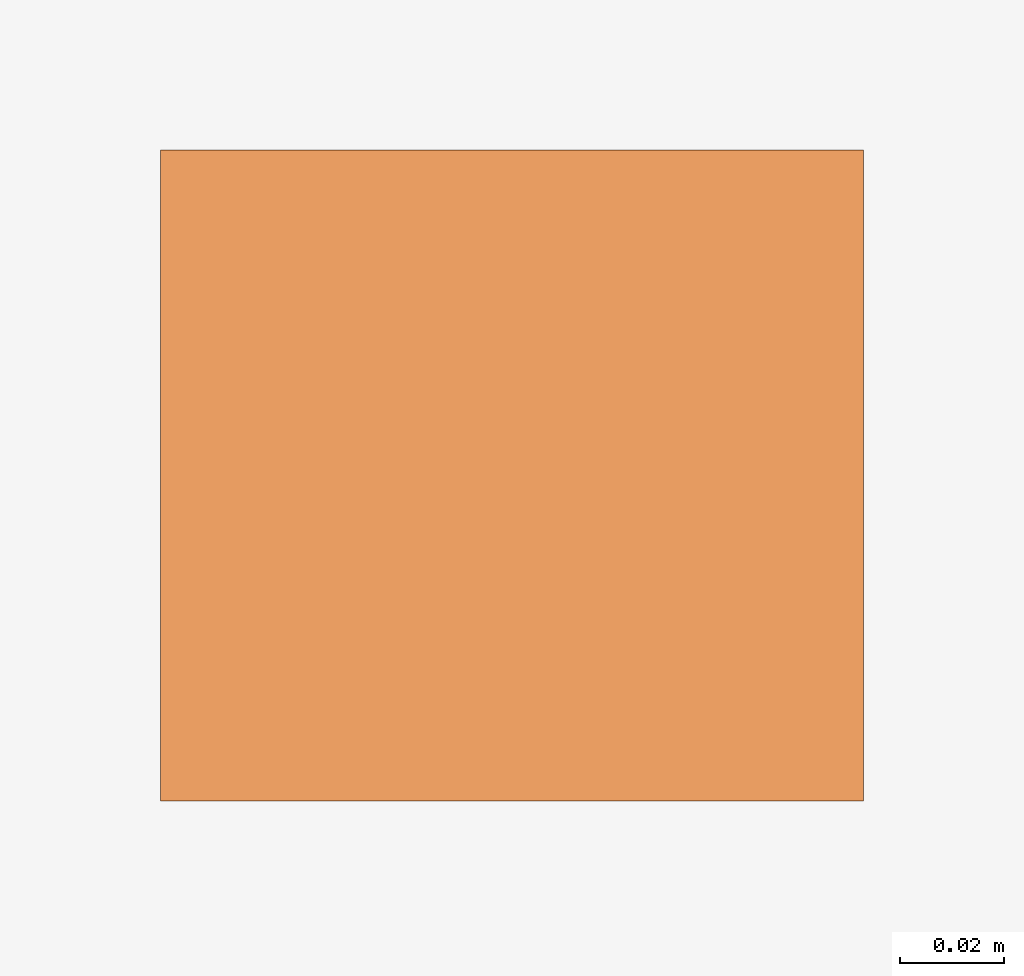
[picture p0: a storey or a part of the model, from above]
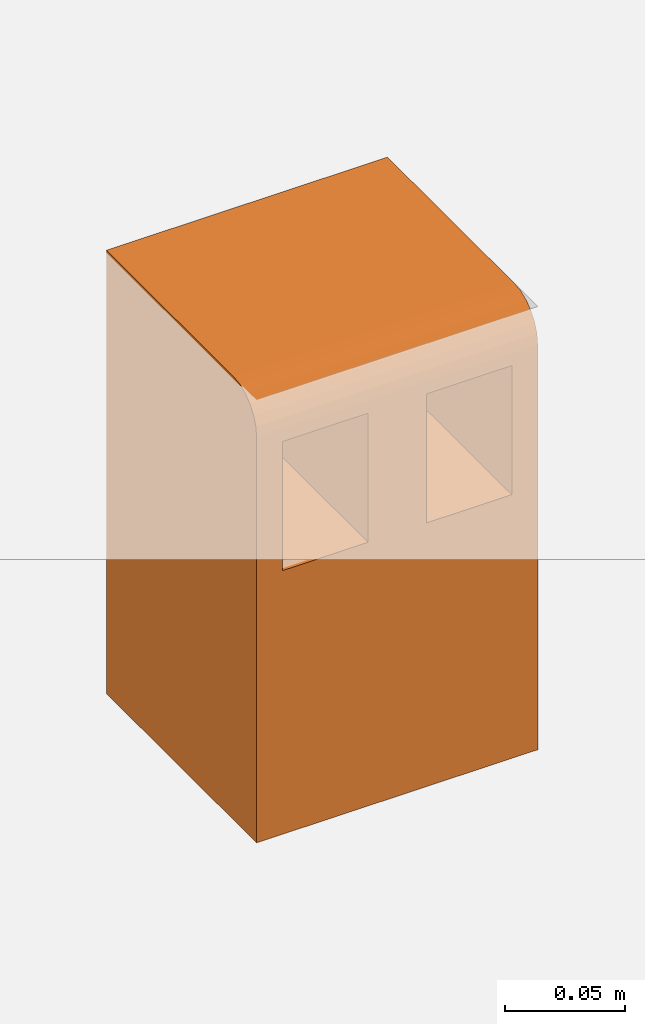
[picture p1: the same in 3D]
Properties of the parts of a building model (IFC2X3)

# File
Description: ViewDefinition [CoordinationView]
File name: 23453 - CFD kerb Outlet Bull Nose.ifc
Time: 2013-10-16T12:22:15
Written by: Autodesk Revit 2013
Made in: 20120221_2030(x64)

# IfcProject, Project Number
LongName: Project Name; Phase: Project Status

# IfcSite, Default
RefLatitude: 42, 21, 30, 344238; RefLongitude: -71, -3, -35, -194702; RefElevation: 0 mm

# IfcBuilding
Pset_BuildingCommon - NumberOfStoreys: 1
Other - Project Address: ## Street City, State Zip; Project Name: Project Name; Project Issue Date: Issue Date; Project Number: Project Number; Client Name: Owner; Project Status: Project Status

# IfcBuildingStorey, Level 1
LongName: Level 1; Elevation: 0 mm
Graphics - Symbol: M_Level Head - Circle: M_Level Head - Circle; Color: 0; Symbol at End 2 Default: yes; Line Pattern: Center; Symbol at End 1 Default: no; Line Weight: 1
Constraints - Elevation Base: 0; Elevation: 0 mm
Identity Data - Name: Level 1; Structural: no; Building Story: yes
Dimensions - Computation Height: 0 mm

# IfcBuildingElementProxy: 23453 - CFD kerb Outlet Bull Nose, Civil-Drainage-Channel-ACO-MultiDrain-M100D-Channel-System:23453 - CFD kerb Outlet Bull Nose:23453 - CFD kerb Outlet Bull Nose:1089344
In: Level 1
Material: Grey Polymer Concrete
Construction - 12673 - Grating - Intercept - Ductile Iron - 500mm Long: no; 12667 - Grating - Perforated - Galvanised Steel - 500mm Long: no; 12680 - Grating - Heelguard™ - Composite Black - 500mm Long: no; 23405 - Grating - Heelguard™ - Ductile Iron - 500mm Long: no; 12656 - Grating - Perforated - Galvanised Steel - 1000mm long: no; 23404 - Universal Endcap - Female End: no; 12619 - Grating - Mesh - Galvanised Steel - 500mm Long: no; 23408 - Grating - Slotted - Ductile Iron - 500mm Long: no; 12610 - Grating - Slotted - Galvanised Steel - 1000mm Long: no; 12666 - Grating - Perforated - Galvanised Steel - 1000mm Long: no; 23406 - Grating - Solid Cover - Ductile Iron - 500mm Long: no; 23409 - Grating - ATec coated - Heelguard™ - Ductile Iron - 500mm Long: no; 12618 - Grating - Mesh - Galvanised Steel - 1000mm Long: no; 23404 - Universal Endcap - Male End: no; 12657 - Grating - Perforated - Galvanised Steel - 500mm long: no; 12611 - Grating - Slotted - Galvanised Steel - 500mm Long: no; 12614 - Grating - Slotted - Galvanised Steel - 1000mm Long: no; 12615 - Grating - Slotted - Galvanised Steel - 500mm Long: no; Shallow Depth Channel: no; 23452 - Kerb Outlet Half Batter: no; Sloping Channel: no; Constant Depth Channel: no; 23453 - Kerb Outlet Bull Nose: yes; 23451 - Downpipe connector 100mm Depth: no; Constant Depth Junction Channel: no; 23450 - Downpipe connector 75mm Depth: no; Sump Unit: no; Shallow Depth Channel with seal: no; Grating 1000mm: no
Constraints - Level: Level: Level 1; Moves With Nearby Elements: no
Dimensions - Length: 125 mm; Volume: 3179082 mm3; EndCap Position: 125 mm; Custom_Value_Length: 875 mm; FloorCut_Length: -125 mm; EndCap_Female_Height: 200 mm; SlopingInvertDepth: 125 mm; SlopingEndOverallDepth: 200 mm; SlopingEndInvertDepth: 130 mm; FloorCut_HorPosition: 67.5 mm; ShallowOverallDepth: 75 mm; SlopingOverallDepth: 195 mm; FloorCut_Width: 135 mm; FloorCut_Depth: 225 mm; EndCap_Height: 200 mm; Endcap_Void_Depth: 6000 mm; ShallowInvDepth: 55 mm; Length Drain: -1000 mm; InvDepth: 80 mm; Depth: 150 mm
Phasing - Phase Created: New Construction
Pset_BuildingElementProxyCommon - Reference: 23453 - CFD kerb Outlet Bull Nose
Model Properties - End Cap Product code 23404: N/A; Grating Product code 12614: N/A; Grating Product code 23406: N/A; Grating Product code 12666: N/A; Grating Product code 12619: N/A; Grating Product code 12667: N/A; Grating Product code 23408: N/A; Grating Product code 12656: N/A; Grating Product code 12673: N/A; Grating Product code 12657: N/A; Grating Product code 12611: N/A; Grating Product code 12615: N/A; Grating Product code 12618: N/A; Grating Product code 23405: N/A; Grating Product code 12610: N/A; Grating Product code 12680: N/A
Identity Data - OmniClass Title: Rainwater Removal; Model Description: Channel drainage system; Address: ACO Business Park, Hitchin Road, Shefford, Bedfordshire, United Kingdom SG17 5TE; Model: ACO MultiDrain MD - M100D; Telephone: +44 (0)1462 816666; URL: www.aco.co.uk; Watermarked By: www.aco.co.uk; e-mail Technical: technical@aco.co.uk; e-mail Sales: customersupport@aco.co.uk; Assembly Description: Rain Water Drainage; Product Code: 23453; Assembly Code: D2040; Fax: +44 (0)1462 815895; Cost: 0; Maintenance guidelines: http://www.aco.co.uk/download.php?id=173; Type Comments: ACO MultiDrain M100D CFD Kerb Outlet Bull Nose Grey; Price: POA - contact ACO; Watermark 2: This file is watermarked and users are prohibited to reproduce, adapt, distribute this information; Watermark 1: This file is the property of ACO Technologies PLC; Watermarked With: BIM Manager Premium Suite; Installation guidelines: http://www.aco.co.uk/download.php?id=173; Product brochure: http://www.aco.co.uk/download.php?id=173; OmniClass Number: 23.70.50.24; Manufacturer: ACO Technologies plc - ACO Water Management Division; Product Page URL: http://www.aco.co.uk/product_detail.php?id=15
Data - Product Dimensions: 125mm x 135mm x225mm (LxWxH); Concrete Surround Volume - Load Class A 15 - Concrete Pavement: N/A; Concrete Surround Volume - Load Class D 400 - Concrete Pavement: N/A; Concrete Surround Volume - Load Class B 125 - C 250 - Concrete Pavement: N/A; Product Weight: 6.95kg; ACO Hydraulic Design Software: N/A; Hydraulic Performance: N/A; Load Class: N/A; Product Standard: N/A; Channel C.S.A: N/A; Pre-formed Outlet Ø: N/A; Installation - Concrete Grade: N/A; Invert Depth: N/A
Materials and Finishes - Edge Rail Material: N/A; Channel Colour: Grey; Edge Rail Finish: N/A; Edge Rail Colour: N/A; Channel Material: Vienite® Synthetic Resin Concrete
Green Building Properties - Channel Recyclable: Fully recyclable; Edge Rail Recyclable: N/A; Edge Rail Recycled Material Content: N/A; Channel Recycled Material Content: 20% minimum
Other - CreatedBy: www.aco.co.uk; Revision: 1
General - SerialNumber: 0; TagNumber: 0

# IfcOpeningElement: Recess
In: Level 1
Dimensions - Perimeter: 20800 mm; Volume: 10808203125 mm3; Thickness: 400 mm; Area: 27030000 mm2
Constraints - Related to Mass: no; Room Bounding: yes; Height Offset From Level: 0 mm; Level: Level: Level 1
Structural - Structural: no; Enable Analytical Model: no
Phasing - Phase Created: New Construction
Construction - Default Thickness: 400 mm; Function: 0
Analytical Properties - Roughness: 1; Absorptance: 0.1
Materials and Finishes - Structural Material: Plant
Graphics - Coarse Scale Fill Color: 0

# IfcSlab: Floor:Generic Floor - 400mm, Floor:Generic Floor - 400mm:193825
In: Level 1
PredefinedType: FLOOR; Material: Plant 400 mm
Dimensions - Perimeter: 20800 mm; Volume: 10808203125 mm3; Thickness: 400 mm; Area: 27030000 mm2
Constraints - Related to Mass: no; Room Bounding: yes; Height Offset From Level: 0 mm; Level: Level: Level 1
Structural - Structural: no; Enable Analytical Model: no
Phasing - Phase Created: New Construction
Pset_SlabCommon - Reference: Generic Floor - 400mm; IsExternal: no; LoadBearing: yes
Construction - Default Thickness: 400 mm; Function: 0
Analytical Properties - Roughness: 1; Absorptance: 0.1
Materials and Finishes - Structural Material: Plant
Graphics - Coarse Scale Fill Color: 0
